# Generated by FakeRAM 2.0
VERSION 5.7 ;
BUSBITCHARS "[]" ;
PROPERTYDEFINITIONS
  MACRO width INTEGER ;
  MACRO depth INTEGER ;
  MACRO banks INTEGER ;
END PROPERTYDEFINITIONS
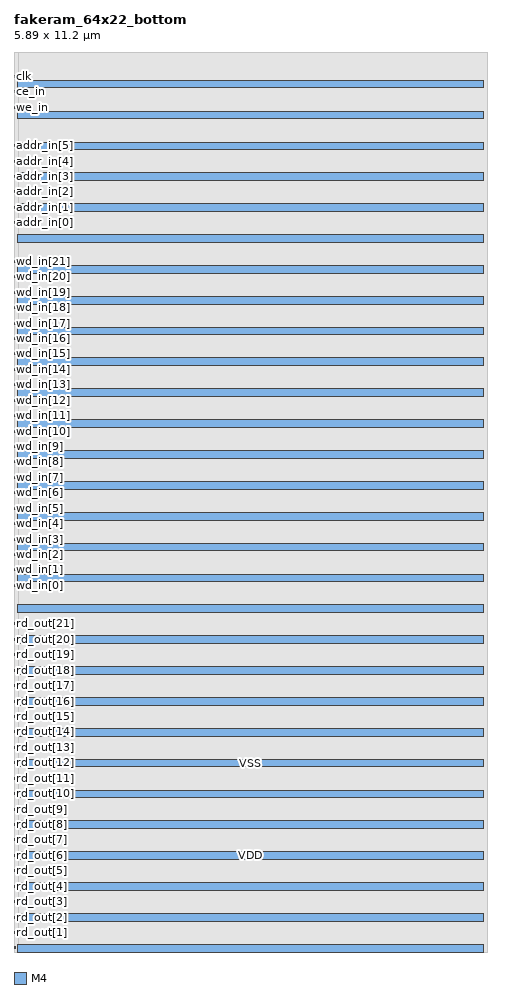
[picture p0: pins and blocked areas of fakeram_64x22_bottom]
MACRO fakeram_64x22_bottom
  PROPERTY width 22 ;
  PROPERTY depth 64 ;
  PROPERTY banks 2 ;
  FOREIGN fakeram_64x22_bottom 0 0 ;
  SYMMETRY X Y R90 ;
  SIZE 5.890 BY 11.200 ;
  CLASS BLOCK ;
  PIN rd_out[0]
    DIRECTION OUTPUT ;
    USE SIGNAL ;
    SHAPE ABUTMENT ;
    PORT
      LAYER M4 ;
      RECT 0.000 0.039 0.024 0.063 ;
    END
  END rd_out[0]
  PIN rd_out[1]
    DIRECTION OUTPUT ;
    USE SIGNAL ;
    SHAPE ABUTMENT ;
    PORT
      LAYER M4 ;
      RECT 0.000 0.231 0.024 0.255 ;
    END
  END rd_out[1]
  PIN rd_out[2]
    DIRECTION OUTPUT ;
    USE SIGNAL ;
    SHAPE ABUTMENT ;
    PORT
      LAYER M4 ;
      RECT 0.000 0.423 0.024 0.447 ;
    END
  END rd_out[2]
  PIN rd_out[3]
    DIRECTION OUTPUT ;
    USE SIGNAL ;
    SHAPE ABUTMENT ;
    PORT
      LAYER M4 ;
      RECT 0.000 0.615 0.024 0.639 ;
    END
  END rd_out[3]
  PIN rd_out[4]
    DIRECTION OUTPUT ;
    USE SIGNAL ;
    SHAPE ABUTMENT ;
    PORT
      LAYER M4 ;
      RECT 0.000 0.807 0.024 0.831 ;
    END
  END rd_out[4]
  PIN rd_out[5]
    DIRECTION OUTPUT ;
    USE SIGNAL ;
    SHAPE ABUTMENT ;
    PORT
      LAYER M4 ;
      RECT 0.000 0.999 0.024 1.023 ;
    END
  END rd_out[5]
  PIN rd_out[6]
    DIRECTION OUTPUT ;
    USE SIGNAL ;
    SHAPE ABUTMENT ;
    PORT
      LAYER M4 ;
      RECT 0.000 1.191 0.024 1.215 ;
    END
  END rd_out[6]
  PIN rd_out[7]
    DIRECTION OUTPUT ;
    USE SIGNAL ;
    SHAPE ABUTMENT ;
    PORT
      LAYER M4 ;
      RECT 0.000 1.383 0.024 1.407 ;
    END
  END rd_out[7]
  PIN rd_out[8]
    DIRECTION OUTPUT ;
    USE SIGNAL ;
    SHAPE ABUTMENT ;
    PORT
      LAYER M4 ;
      RECT 0.000 1.575 0.024 1.599 ;
    END
  END rd_out[8]
  PIN rd_out[9]
    DIRECTION OUTPUT ;
    USE SIGNAL ;
    SHAPE ABUTMENT ;
    PORT
      LAYER M4 ;
      RECT 0.000 1.767 0.024 1.791 ;
    END
  END rd_out[9]
  PIN rd_out[10]
    DIRECTION OUTPUT ;
    USE SIGNAL ;
    SHAPE ABUTMENT ;
    PORT
      LAYER M4 ;
      RECT 0.000 1.959 0.024 1.983 ;
    END
  END rd_out[10]
  PIN rd_out[11]
    DIRECTION OUTPUT ;
    USE SIGNAL ;
    SHAPE ABUTMENT ;
    PORT
      LAYER M4 ;
      RECT 0.000 2.151 0.024 2.175 ;
    END
  END rd_out[11]
  PIN rd_out[12]
    DIRECTION OUTPUT ;
    USE SIGNAL ;
    SHAPE ABUTMENT ;
    PORT
      LAYER M4 ;
      RECT 0.000 2.343 0.024 2.367 ;
    END
  END rd_out[12]
  PIN rd_out[13]
    DIRECTION OUTPUT ;
    USE SIGNAL ;
    SHAPE ABUTMENT ;
    PORT
      LAYER M4 ;
      RECT 0.000 2.535 0.024 2.559 ;
    END
  END rd_out[13]
  PIN rd_out[14]
    DIRECTION OUTPUT ;
    USE SIGNAL ;
    SHAPE ABUTMENT ;
    PORT
      LAYER M4 ;
      RECT 0.000 2.727 0.024 2.751 ;
    END
  END rd_out[14]
  PIN rd_out[15]
    DIRECTION OUTPUT ;
    USE SIGNAL ;
    SHAPE ABUTMENT ;
    PORT
      LAYER M4 ;
      RECT 0.000 2.919 0.024 2.943 ;
    END
  END rd_out[15]
  PIN rd_out[16]
    DIRECTION OUTPUT ;
    USE SIGNAL ;
    SHAPE ABUTMENT ;
    PORT
      LAYER M4 ;
      RECT 0.000 3.111 0.024 3.135 ;
    END
  END rd_out[16]
  PIN rd_out[17]
    DIRECTION OUTPUT ;
    USE SIGNAL ;
    SHAPE ABUTMENT ;
    PORT
      LAYER M4 ;
      RECT 0.000 3.303 0.024 3.327 ;
    END
  END rd_out[17]
  PIN rd_out[18]
    DIRECTION OUTPUT ;
    USE SIGNAL ;
    SHAPE ABUTMENT ;
    PORT
      LAYER M4 ;
      RECT 0.000 3.495 0.024 3.519 ;
    END
  END rd_out[18]
  PIN rd_out[19]
    DIRECTION OUTPUT ;
    USE SIGNAL ;
    SHAPE ABUTMENT ;
    PORT
      LAYER M4 ;
      RECT 0.000 3.687 0.024 3.711 ;
    END
  END rd_out[19]
  PIN rd_out[20]
    DIRECTION OUTPUT ;
    USE SIGNAL ;
    SHAPE ABUTMENT ;
    PORT
      LAYER M4 ;
      RECT 0.000 3.879 0.024 3.903 ;
    END
  END rd_out[20]
  PIN rd_out[21]
    DIRECTION OUTPUT ;
    USE SIGNAL ;
    SHAPE ABUTMENT ;
    PORT
      LAYER M4 ;
      RECT 0.000 4.071 0.024 4.095 ;
    END
  END rd_out[21]
  PIN wd_in[0]
    DIRECTION INPUT ;
    USE SIGNAL ;
    SHAPE ABUTMENT ;
    PORT
      LAYER M4 ;
      RECT 0.000 4.551 0.024 4.575 ;
    END
  END wd_in[0]
  PIN wd_in[1]
    DIRECTION INPUT ;
    USE SIGNAL ;
    SHAPE ABUTMENT ;
    PORT
      LAYER M4 ;
      RECT 0.000 4.743 0.024 4.767 ;
    END
  END wd_in[1]
  PIN wd_in[2]
    DIRECTION INPUT ;
    USE SIGNAL ;
    SHAPE ABUTMENT ;
    PORT
      LAYER M4 ;
      RECT 0.000 4.935 0.024 4.959 ;
    END
  END wd_in[2]
  PIN wd_in[3]
    DIRECTION INPUT ;
    USE SIGNAL ;
    SHAPE ABUTMENT ;
    PORT
      LAYER M4 ;
      RECT 0.000 5.127 0.024 5.151 ;
    END
  END wd_in[3]
  PIN wd_in[4]
    DIRECTION INPUT ;
    USE SIGNAL ;
    SHAPE ABUTMENT ;
    PORT
      LAYER M4 ;
      RECT 0.000 5.319 0.024 5.343 ;
    END
  END wd_in[4]
  PIN wd_in[5]
    DIRECTION INPUT ;
    USE SIGNAL ;
    SHAPE ABUTMENT ;
    PORT
      LAYER M4 ;
      RECT 0.000 5.511 0.024 5.535 ;
    END
  END wd_in[5]
  PIN wd_in[6]
    DIRECTION INPUT ;
    USE SIGNAL ;
    SHAPE ABUTMENT ;
    PORT
      LAYER M4 ;
      RECT 0.000 5.703 0.024 5.727 ;
    END
  END wd_in[6]
  PIN wd_in[7]
    DIRECTION INPUT ;
    USE SIGNAL ;
    SHAPE ABUTMENT ;
    PORT
      LAYER M4 ;
      RECT 0.000 5.895 0.024 5.919 ;
    END
  END wd_in[7]
  PIN wd_in[8]
    DIRECTION INPUT ;
    USE SIGNAL ;
    SHAPE ABUTMENT ;
    PORT
      LAYER M4 ;
      RECT 0.000 6.087 0.024 6.111 ;
    END
  END wd_in[8]
  PIN wd_in[9]
    DIRECTION INPUT ;
    USE SIGNAL ;
    SHAPE ABUTMENT ;
    PORT
      LAYER M4 ;
      RECT 0.000 6.279 0.024 6.303 ;
    END
  END wd_in[9]
  PIN wd_in[10]
    DIRECTION INPUT ;
    USE SIGNAL ;
    SHAPE ABUTMENT ;
    PORT
      LAYER M4 ;
      RECT 0.000 6.471 0.024 6.495 ;
    END
  END wd_in[10]
  PIN wd_in[11]
    DIRECTION INPUT ;
    USE SIGNAL ;
    SHAPE ABUTMENT ;
    PORT
      LAYER M4 ;
      RECT 0.000 6.663 0.024 6.687 ;
    END
  END wd_in[11]
  PIN wd_in[12]
    DIRECTION INPUT ;
    USE SIGNAL ;
    SHAPE ABUTMENT ;
    PORT
      LAYER M4 ;
      RECT 0.000 6.855 0.024 6.879 ;
    END
  END wd_in[12]
  PIN wd_in[13]
    DIRECTION INPUT ;
    USE SIGNAL ;
    SHAPE ABUTMENT ;
    PORT
      LAYER M4 ;
      RECT 0.000 7.047 0.024 7.071 ;
    END
  END wd_in[13]
  PIN wd_in[14]
    DIRECTION INPUT ;
    USE SIGNAL ;
    SHAPE ABUTMENT ;
    PORT
      LAYER M4 ;
      RECT 0.000 7.239 0.024 7.263 ;
    END
  END wd_in[14]
  PIN wd_in[15]
    DIRECTION INPUT ;
    USE SIGNAL ;
    SHAPE ABUTMENT ;
    PORT
      LAYER M4 ;
      RECT 0.000 7.431 0.024 7.455 ;
    END
  END wd_in[15]
  PIN wd_in[16]
    DIRECTION INPUT ;
    USE SIGNAL ;
    SHAPE ABUTMENT ;
    PORT
      LAYER M4 ;
      RECT 0.000 7.623 0.024 7.647 ;
    END
  END wd_in[16]
  PIN wd_in[17]
    DIRECTION INPUT ;
    USE SIGNAL ;
    SHAPE ABUTMENT ;
    PORT
      LAYER M4 ;
      RECT 0.000 7.815 0.024 7.839 ;
    END
  END wd_in[17]
  PIN wd_in[18]
    DIRECTION INPUT ;
    USE SIGNAL ;
    SHAPE ABUTMENT ;
    PORT
      LAYER M4 ;
      RECT 0.000 8.007 0.024 8.031 ;
    END
  END wd_in[18]
  PIN wd_in[19]
    DIRECTION INPUT ;
    USE SIGNAL ;
    SHAPE ABUTMENT ;
    PORT
      LAYER M4 ;
      RECT 0.000 8.199 0.024 8.223 ;
    END
  END wd_in[19]
  PIN wd_in[20]
    DIRECTION INPUT ;
    USE SIGNAL ;
    SHAPE ABUTMENT ;
    PORT
      LAYER M4 ;
      RECT 0.000 8.391 0.024 8.415 ;
    END
  END wd_in[20]
  PIN wd_in[21]
    DIRECTION INPUT ;
    USE SIGNAL ;
    SHAPE ABUTMENT ;
    PORT
      LAYER M4 ;
      RECT 0.000 8.583 0.024 8.607 ;
    END
  END wd_in[21]
  PIN addr_in[0]
    DIRECTION INPUT ;
    USE SIGNAL ;
    SHAPE ABUTMENT ;
    PORT
      LAYER M4 ;
      RECT 0.000 9.063 0.024 9.087 ;
    END
  END addr_in[0]
  PIN addr_in[1]
    DIRECTION INPUT ;
    USE SIGNAL ;
    SHAPE ABUTMENT ;
    PORT
      LAYER M4 ;
      RECT 0.000 9.255 0.024 9.279 ;
    END
  END addr_in[1]
  PIN addr_in[2]
    DIRECTION INPUT ;
    USE SIGNAL ;
    SHAPE ABUTMENT ;
    PORT
      LAYER M4 ;
      RECT 0.000 9.447 0.024 9.471 ;
    END
  END addr_in[2]
  PIN addr_in[3]
    DIRECTION INPUT ;
    USE SIGNAL ;
    SHAPE ABUTMENT ;
    PORT
      LAYER M4 ;
      RECT 0.000 9.639 0.024 9.663 ;
    END
  END addr_in[3]
  PIN addr_in[4]
    DIRECTION INPUT ;
    USE SIGNAL ;
    SHAPE ABUTMENT ;
    PORT
      LAYER M4 ;
      RECT 0.000 9.831 0.024 9.855 ;
    END
  END addr_in[4]
  PIN addr_in[5]
    DIRECTION INPUT ;
    USE SIGNAL ;
    SHAPE ABUTMENT ;
    PORT
      LAYER M4 ;
      RECT 0.000 10.023 0.024 10.047 ;
    END
  END addr_in[5]
  PIN we_in
    DIRECTION INPUT ;
    USE SIGNAL ;
    SHAPE ABUTMENT ;
    PORT
      LAYER M4 ;
      RECT 0.000 10.503 0.024 10.527 ;
    END
  END we_in
  PIN ce_in
    DIRECTION INPUT ;
    USE SIGNAL ;
    SHAPE ABUTMENT ;
    PORT
      LAYER M4 ;
      RECT 0.000 10.695 0.024 10.719 ;
    END
  END ce_in
  PIN clk
    DIRECTION INPUT ;
    USE SIGNAL ;
    SHAPE ABUTMENT ;
    PORT
      LAYER M4 ;
      RECT 0.000 10.887 0.024 10.911 ;
    END
  END clk
  PIN VSS
    DIRECTION INOUT ;
    USE GROUND ;
    PORT
      LAYER M4 ;
      RECT 0.048 0.000 5.842 0.096 ;
      RECT 0.048 0.768 5.842 0.864 ;
      RECT 0.048 1.536 5.842 1.632 ;
      RECT 0.048 2.304 5.842 2.400 ;
      RECT 0.048 3.072 5.842 3.168 ;
      RECT 0.048 3.840 5.842 3.936 ;
      RECT 0.048 4.608 5.842 4.704 ;
      RECT 0.048 5.376 5.842 5.472 ;
      RECT 0.048 6.144 5.842 6.240 ;
      RECT 0.048 6.912 5.842 7.008 ;
      RECT 0.048 7.680 5.842 7.776 ;
      RECT 0.048 8.448 5.842 8.544 ;
      RECT 0.048 9.216 5.842 9.312 ;
      RECT 0.048 9.984 5.842 10.080 ;
      RECT 0.048 10.752 5.842 10.848 ;
    END
  END VSS
  PIN VDD
    DIRECTION INOUT ;
    USE POWER ;
    PORT
      LAYER M4 ;
      RECT 0.048 0.384 5.842 0.480 ;
      RECT 0.048 1.152 5.842 1.248 ;
      RECT 0.048 1.920 5.842 2.016 ;
      RECT 0.048 2.688 5.842 2.784 ;
      RECT 0.048 3.456 5.842 3.552 ;
      RECT 0.048 4.224 5.842 4.320 ;
      RECT 0.048 4.992 5.842 5.088 ;
      RECT 0.048 5.760 5.842 5.856 ;
      RECT 0.048 6.528 5.842 6.624 ;
      RECT 0.048 7.296 5.842 7.392 ;
      RECT 0.048 8.064 5.842 8.160 ;
      RECT 0.048 8.832 5.842 8.928 ;
      RECT 0.048 9.600 5.842 9.696 ;
      RECT 0.048 10.368 5.842 10.464 ;
    END
  END VDD
  OBS
    LAYER M1 ;
    RECT 0 0 5.890 11.200 ;
    LAYER M2 ;
    RECT 0 0 5.890 11.200 ;
    LAYER M3 ;
    RECT 0.059 0.000 5.890 11.200 ;
    LAYER M4 ;
    RECT 0.059 0.000 5.890 11.200 ;
  END
END fakeram_64x22_bottom

END LIBRARY
